VERSION 5.7 ;
  NOWIREEXTENSIONATPIN ON ;
  DIVIDERCHAR "/" ;
  BUSBITCHARS "[]" ;
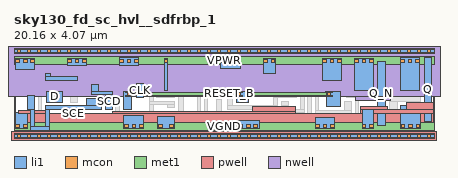
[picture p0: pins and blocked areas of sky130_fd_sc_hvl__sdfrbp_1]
MACRO sky130_fd_sc_hvl__sdfrbp_1
  CLASS BLOCK ;
  FOREIGN sky130_fd_sc_hvl__sdfrbp_1 ;
  ORIGIN 0.000 0.000 ;
  SIZE 20.160 BY 4.070 ;
  PIN CLK
    ANTENNAGATEAREA 0.585000 ;
    PORT
      LAYER li1 ;
        RECT 5.870 1.850 6.200 2.520 ;
    END
  END CLK
  PIN D
    ANTENNAGATEAREA 0.420000 ;
    PORT
      LAYER li1 ;
        RECT 1.565 1.625 2.330 2.135 ;
    END
  END D
  PIN RESET_B
    ANTENNAGATEAREA 1.260000 ;
    PORT
      LAYER li1 ;
        RECT 5.235 1.295 5.635 2.150 ;
        RECT 10.685 1.625 11.245 2.135 ;
        RECT 15.005 1.425 15.685 2.120 ;
      LAYER mcon ;
        RECT 5.435 1.950 5.605 2.120 ;
        RECT 10.715 1.950 10.885 2.120 ;
        RECT 15.035 1.950 15.205 2.120 ;
      LAYER met1 ;
        RECT 5.375 2.105 5.665 2.150 ;
        RECT 10.655 2.105 10.945 2.150 ;
        RECT 14.975 2.105 15.265 2.150 ;
        RECT 5.375 1.965 15.265 2.105 ;
        RECT 5.375 1.920 5.665 1.965 ;
        RECT 10.655 1.920 10.945 1.965 ;
        RECT 14.975 1.920 15.265 1.965 ;
    END
  END RESET_B
  PIN SCD
    ANTENNAGATEAREA 0.420000 ;
    PORT
      LAYER li1 ;
        RECT 3.710 2.155 4.040 2.480 ;
        RECT 3.710 1.975 4.705 2.155 ;
        RECT 4.375 1.295 4.705 1.975 ;
    END
  END SCD
  PIN SCE
    ANTENNAGATEAREA 0.840000 ;
    PORT
      LAYER li1 ;
        RECT 1.515 2.835 1.765 2.995 ;
        RECT 1.515 2.665 3.040 2.835 ;
        RECT 0.655 1.295 0.985 1.965 ;
        RECT 3.485 1.445 4.195 1.795 ;
        RECT 0.815 0.435 0.985 1.295 ;
        RECT 1.515 1.275 4.195 1.445 ;
        RECT 1.515 0.435 1.685 1.275 ;
        RECT 0.815 0.265 1.685 0.435 ;
    END
  END SCE
  PIN VGND
    USE GROUND ;
    PORT
      LAYER li1 ;
        RECT 0.090 0.365 0.635 1.115 ;
        RECT 5.275 0.365 6.225 0.995 ;
        RECT 6.870 0.365 7.720 0.915 ;
        RECT 10.770 0.365 11.805 0.745 ;
        RECT 14.450 0.365 15.400 0.895 ;
        RECT 16.725 0.365 17.255 1.305 ;
        RECT 18.565 0.365 19.515 1.475 ;
      LAYER mcon ;
        RECT 0.095 0.395 0.265 0.565 ;
        RECT 0.455 0.395 0.625 0.565 ;
        RECT 5.305 0.395 5.475 0.565 ;
        RECT 5.665 0.395 5.835 0.565 ;
        RECT 6.025 0.395 6.195 0.565 ;
        RECT 6.950 0.395 7.120 0.565 ;
        RECT 7.470 0.395 7.640 0.565 ;
        RECT 10.800 0.395 10.970 0.565 ;
        RECT 11.160 0.395 11.330 0.565 ;
        RECT 11.520 0.395 11.690 0.565 ;
        RECT 14.480 0.395 14.650 0.565 ;
        RECT 14.840 0.395 15.010 0.565 ;
        RECT 15.200 0.395 15.370 0.565 ;
        RECT 16.725 0.395 16.895 0.565 ;
        RECT 17.085 0.395 17.255 0.565 ;
        RECT 18.595 0.395 18.765 0.565 ;
        RECT 18.955 0.395 19.125 0.565 ;
        RECT 19.315 0.395 19.485 0.565 ;
      LAYER met1 ;
        RECT 0.000 0.255 20.160 0.625 ;
    END
  END VGND
  PIN VNB
    ANTENNADIFFAREA 3.427200 ;
    PORT
      LAYER pwell ;
        RECT 0.195 1.085 1.525 1.205 ;
        RECT 11.460 1.180 13.515 1.415 ;
        RECT 4.735 1.085 13.515 1.180 ;
        RECT 16.635 1.255 17.925 1.415 ;
        RECT 18.840 1.255 20.130 1.585 ;
        RECT 16.635 1.085 20.130 1.255 ;
        RECT 0.195 0.215 20.130 1.085 ;
        RECT -0.130 -0.215 20.290 0.215 ;
      LAYER li1 ;
        RECT 0.000 -0.085 20.160 0.085 ;
      LAYER mcon ;
        RECT 0.155 -0.085 0.325 0.085 ;
        RECT 0.635 -0.085 0.805 0.085 ;
        RECT 1.115 -0.085 1.285 0.085 ;
        RECT 1.595 -0.085 1.765 0.085 ;
        RECT 2.075 -0.085 2.245 0.085 ;
        RECT 2.555 -0.085 2.725 0.085 ;
        RECT 3.035 -0.085 3.205 0.085 ;
        RECT 3.515 -0.085 3.685 0.085 ;
        RECT 3.995 -0.085 4.165 0.085 ;
        RECT 4.475 -0.085 4.645 0.085 ;
        RECT 4.955 -0.085 5.125 0.085 ;
        RECT 5.435 -0.085 5.605 0.085 ;
        RECT 5.915 -0.085 6.085 0.085 ;
        RECT 6.395 -0.085 6.565 0.085 ;
        RECT 6.875 -0.085 7.045 0.085 ;
        RECT 7.355 -0.085 7.525 0.085 ;
        RECT 7.835 -0.085 8.005 0.085 ;
        RECT 8.315 -0.085 8.485 0.085 ;
        RECT 8.795 -0.085 8.965 0.085 ;
        RECT 9.275 -0.085 9.445 0.085 ;
        RECT 9.755 -0.085 9.925 0.085 ;
        RECT 10.235 -0.085 10.405 0.085 ;
        RECT 10.715 -0.085 10.885 0.085 ;
        RECT 11.195 -0.085 11.365 0.085 ;
        RECT 11.675 -0.085 11.845 0.085 ;
        RECT 12.155 -0.085 12.325 0.085 ;
        RECT 12.635 -0.085 12.805 0.085 ;
        RECT 13.115 -0.085 13.285 0.085 ;
        RECT 13.595 -0.085 13.765 0.085 ;
        RECT 14.075 -0.085 14.245 0.085 ;
        RECT 14.555 -0.085 14.725 0.085 ;
        RECT 15.035 -0.085 15.205 0.085 ;
        RECT 15.515 -0.085 15.685 0.085 ;
        RECT 15.995 -0.085 16.165 0.085 ;
        RECT 16.475 -0.085 16.645 0.085 ;
        RECT 16.955 -0.085 17.125 0.085 ;
        RECT 17.435 -0.085 17.605 0.085 ;
        RECT 17.915 -0.085 18.085 0.085 ;
        RECT 18.395 -0.085 18.565 0.085 ;
        RECT 18.875 -0.085 19.045 0.085 ;
        RECT 19.355 -0.085 19.525 0.085 ;
        RECT 19.835 -0.085 20.005 0.085 ;
      LAYER met1 ;
        RECT 0.000 -0.115 20.160 0.115 ;
    END
  END VNB
  PIN VPB
    ANTENNADIFFAREA 3.427200 ;
    PORT
      LAYER nwell ;
        RECT -0.330 1.885 20.490 4.485 ;
        RECT 16.405 1.720 18.095 1.885 ;
      LAYER li1 ;
        RECT 0.000 3.985 20.160 4.155 ;
      LAYER mcon ;
        RECT 0.155 3.985 0.325 4.155 ;
        RECT 0.635 3.985 0.805 4.155 ;
        RECT 1.115 3.985 1.285 4.155 ;
        RECT 1.595 3.985 1.765 4.155 ;
        RECT 2.075 3.985 2.245 4.155 ;
        RECT 2.555 3.985 2.725 4.155 ;
        RECT 3.035 3.985 3.205 4.155 ;
        RECT 3.515 3.985 3.685 4.155 ;
        RECT 3.995 3.985 4.165 4.155 ;
        RECT 4.475 3.985 4.645 4.155 ;
        RECT 4.955 3.985 5.125 4.155 ;
        RECT 5.435 3.985 5.605 4.155 ;
        RECT 5.915 3.985 6.085 4.155 ;
        RECT 6.395 3.985 6.565 4.155 ;
        RECT 6.875 3.985 7.045 4.155 ;
        RECT 7.355 3.985 7.525 4.155 ;
        RECT 7.835 3.985 8.005 4.155 ;
        RECT 8.315 3.985 8.485 4.155 ;
        RECT 8.795 3.985 8.965 4.155 ;
        RECT 9.275 3.985 9.445 4.155 ;
        RECT 9.755 3.985 9.925 4.155 ;
        RECT 10.235 3.985 10.405 4.155 ;
        RECT 10.715 3.985 10.885 4.155 ;
        RECT 11.195 3.985 11.365 4.155 ;
        RECT 11.675 3.985 11.845 4.155 ;
        RECT 12.155 3.985 12.325 4.155 ;
        RECT 12.635 3.985 12.805 4.155 ;
        RECT 13.115 3.985 13.285 4.155 ;
        RECT 13.595 3.985 13.765 4.155 ;
        RECT 14.075 3.985 14.245 4.155 ;
        RECT 14.555 3.985 14.725 4.155 ;
        RECT 15.035 3.985 15.205 4.155 ;
        RECT 15.515 3.985 15.685 4.155 ;
        RECT 15.995 3.985 16.165 4.155 ;
        RECT 16.475 3.985 16.645 4.155 ;
        RECT 16.955 3.985 17.125 4.155 ;
        RECT 17.435 3.985 17.605 4.155 ;
        RECT 17.915 3.985 18.085 4.155 ;
        RECT 18.395 3.985 18.565 4.155 ;
        RECT 18.875 3.985 19.045 4.155 ;
        RECT 19.355 3.985 19.525 4.155 ;
        RECT 19.835 3.985 20.005 4.155 ;
      LAYER met1 ;
        RECT 0.000 3.955 20.160 4.185 ;
    END
  END VPB
  PIN VPWR
    USE POWER ;
    PORT
      LAYER li1 ;
        RECT 0.090 3.205 0.985 3.705 ;
        RECT 2.545 3.365 3.495 3.735 ;
        RECT 5.085 3.365 5.975 3.755 ;
        RECT 7.205 2.205 7.375 3.705 ;
        RECT 9.925 3.255 10.875 3.755 ;
        RECT 11.955 3.015 12.545 3.735 ;
        RECT 14.800 2.675 15.720 3.705 ;
        RECT 16.330 2.185 17.255 3.705 ;
        RECT 18.535 2.175 19.485 3.755 ;
      LAYER mcon ;
        RECT 0.095 3.505 0.265 3.675 ;
        RECT 0.455 3.505 0.625 3.675 ;
        RECT 0.815 3.505 0.985 3.675 ;
        RECT 2.575 3.505 2.745 3.675 ;
        RECT 2.935 3.505 3.105 3.675 ;
        RECT 3.295 3.505 3.465 3.675 ;
        RECT 5.085 3.505 5.255 3.675 ;
        RECT 5.445 3.505 5.615 3.675 ;
        RECT 5.805 3.505 5.975 3.675 ;
        RECT 7.205 3.505 7.375 3.675 ;
        RECT 9.955 3.505 10.125 3.675 ;
        RECT 10.315 3.505 10.485 3.675 ;
        RECT 10.675 3.505 10.845 3.675 ;
        RECT 11.985 3.505 12.155 3.675 ;
        RECT 12.345 3.505 12.515 3.675 ;
        RECT 14.815 3.505 14.985 3.675 ;
        RECT 15.175 3.505 15.345 3.675 ;
        RECT 15.535 3.505 15.705 3.675 ;
        RECT 16.345 3.505 16.515 3.675 ;
        RECT 16.705 3.505 16.875 3.675 ;
        RECT 17.065 3.505 17.235 3.675 ;
        RECT 18.565 3.505 18.735 3.675 ;
        RECT 18.925 3.505 19.095 3.675 ;
        RECT 19.285 3.505 19.455 3.675 ;
      LAYER met1 ;
        RECT 0.000 3.445 20.160 3.815 ;
    END
  END VPWR
  PIN Q
    ANTENNADIFFAREA 0.626250 ;
    PORT
      LAYER li1 ;
        RECT 19.700 0.685 20.040 3.755 ;
    END
  END Q
  PIN Q_N
    ANTENNADIFFAREA 0.596250 ;
    PORT
      LAYER li1 ;
        RECT 17.435 0.515 17.835 3.570 ;
    END
  END Q_N
  OBS
      LAYER li1 ;
        RECT 1.165 3.205 1.415 3.705 ;
        RECT 1.675 3.235 2.115 3.735 ;
        RECT 1.165 2.485 1.335 3.205 ;
        RECT 1.945 3.185 2.115 3.235 ;
        RECT 4.655 3.185 4.905 3.735 ;
        RECT 6.155 3.635 7.025 3.805 ;
        RECT 6.155 3.185 6.325 3.635 ;
        RECT 1.945 3.015 6.325 3.185 ;
        RECT 3.270 2.665 4.680 2.835 ;
        RECT 3.270 2.485 3.440 2.665 ;
        RECT 1.165 2.315 3.440 2.485 ;
        RECT 4.350 2.325 4.680 2.665 ;
        RECT 1.165 0.615 1.335 2.315 ;
        RECT 2.730 1.625 3.060 2.315 ;
        RECT 4.885 1.095 5.055 3.015 ;
        RECT 1.865 0.435 2.115 0.995 ;
        RECT 3.275 0.925 5.055 1.095 ;
        RECT 6.505 1.675 6.675 3.455 ;
        RECT 6.855 2.025 7.025 3.635 ;
        RECT 8.275 3.425 8.605 3.755 ;
        RECT 7.555 3.255 8.955 3.425 ;
        RECT 7.555 2.025 7.725 3.255 ;
        RECT 8.355 3.015 8.605 3.075 ;
        RECT 6.855 1.855 7.725 2.025 ;
        RECT 7.905 2.225 8.605 3.015 ;
        RECT 6.505 1.505 7.695 1.675 ;
        RECT 3.275 0.615 3.605 0.925 ;
        RECT 4.765 0.435 5.095 0.755 ;
        RECT 6.505 0.495 6.675 1.505 ;
        RECT 7.365 1.345 7.695 1.505 ;
        RECT 7.905 0.995 8.150 2.225 ;
        RECT 8.785 0.995 8.955 3.255 ;
        RECT 1.865 0.265 5.095 0.435 ;
        RECT 7.900 0.435 8.150 0.995 ;
        RECT 8.410 0.615 8.955 0.995 ;
        RECT 9.135 3.075 9.385 3.755 ;
        RECT 11.325 3.075 11.775 3.735 ;
        RECT 9.135 2.905 11.775 3.075 ;
        RECT 9.135 0.995 9.305 2.905 ;
        RECT 11.325 2.835 11.775 2.905 ;
        RECT 9.510 2.485 9.840 2.675 ;
        RECT 11.325 2.665 11.945 2.835 ;
        RECT 9.510 2.315 11.595 2.485 ;
        RECT 9.510 2.005 9.840 2.315 ;
        RECT 11.425 2.045 11.595 2.315 ;
        RECT 11.775 2.225 11.945 2.665 ;
        RECT 12.735 2.695 12.985 3.755 ;
        RECT 13.435 3.045 13.765 3.755 ;
        RECT 13.435 2.875 14.620 3.045 ;
        RECT 12.735 2.525 13.570 2.695 ;
        RECT 12.125 2.175 13.220 2.345 ;
        RECT 12.125 2.045 12.295 2.175 ;
        RECT 9.700 1.095 9.975 1.755 ;
        RECT 10.225 1.445 10.505 1.945 ;
        RECT 11.425 1.875 12.295 2.045 ;
        RECT 13.400 1.995 13.570 2.525 ;
        RECT 12.475 1.825 13.570 1.995 ;
        RECT 12.475 1.445 12.645 1.825 ;
        RECT 10.225 1.275 12.645 1.445 ;
        RECT 9.135 0.615 9.520 0.995 ;
        RECT 9.700 0.925 12.145 1.095 ;
        RECT 9.700 0.435 9.975 0.925 ;
        RECT 7.900 0.265 9.975 0.435 ;
        RECT 11.975 0.435 12.145 0.925 ;
        RECT 12.315 0.615 12.645 1.275 ;
        RECT 12.825 1.475 13.155 1.645 ;
        RECT 12.825 0.435 12.995 1.475 ;
        RECT 13.750 1.295 13.920 2.875 ;
        RECT 13.175 1.125 13.920 1.295 ;
        RECT 13.175 0.615 13.425 1.125 ;
        RECT 14.100 0.435 14.270 2.555 ;
        RECT 14.450 1.245 14.620 2.875 ;
        RECT 15.900 2.495 16.150 3.175 ;
        RECT 14.800 2.300 16.150 2.495 ;
        RECT 15.980 2.005 16.150 2.300 ;
        RECT 15.980 1.835 16.545 2.005 ;
        RECT 15.865 1.245 16.195 1.655 ;
        RECT 14.450 1.075 16.195 1.245 ;
        RECT 16.375 0.895 16.545 1.835 ;
        RECT 16.175 0.515 16.545 0.895 ;
        RECT 18.025 1.985 18.355 2.985 ;
        RECT 18.025 1.655 19.520 1.985 ;
        RECT 18.025 0.685 18.385 1.655 ;
        RECT 11.975 0.265 14.270 0.435 ;
  END
END sky130_fd_sc_hvl__sdfrbp_1
END LIBRARY

